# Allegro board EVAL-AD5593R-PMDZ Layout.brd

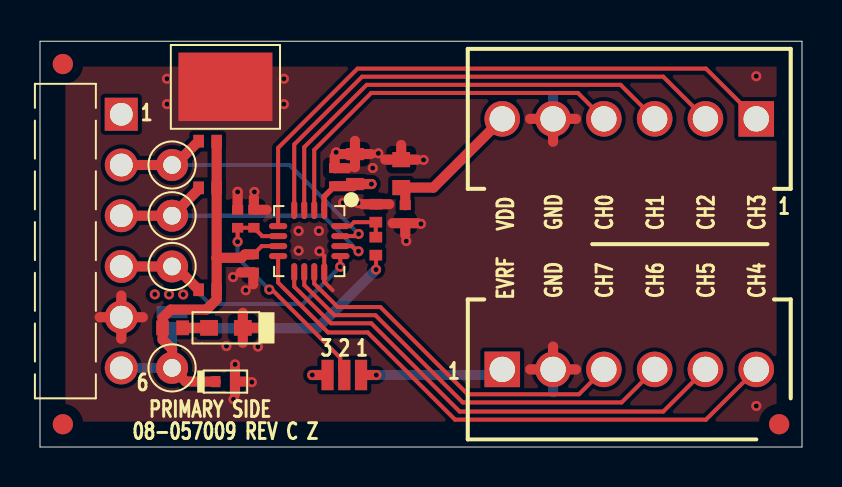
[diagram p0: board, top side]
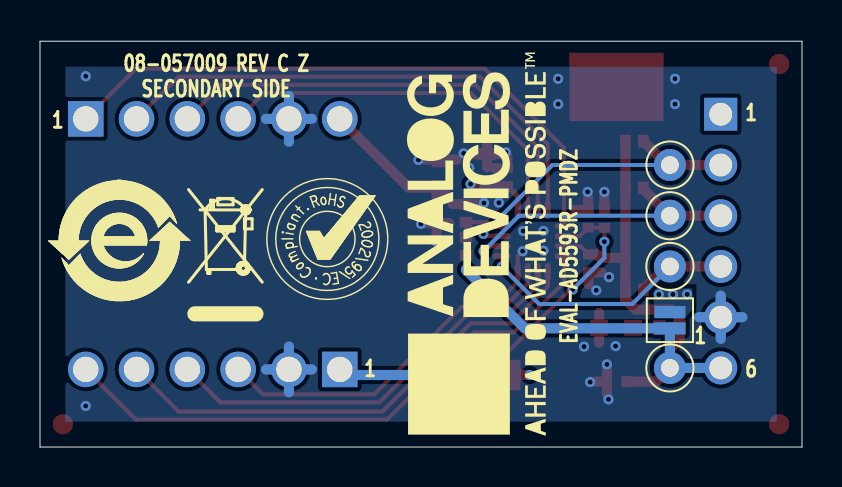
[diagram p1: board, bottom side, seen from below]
Outline 38.1 x 20.32 mm; copper layers: TOP, L2_GND, L3_PWR, BOTTOM. Coordinates in mm from the lower left corner of the outline.
Outline path: 0,20.32 0,0 38.1,0 38.1,20.32 0,20.32

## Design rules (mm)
constraint set DEFAULT: min track width 0.203

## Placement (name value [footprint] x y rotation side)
C1  1UF  [C0402]  10.69 11.43 270 top
C2  0.1UF  [C0402]  9.88 11.43 270 top
C3  0.1UF  [C0402]  14.73 13.51 90 top
C4  10UF  [C0603H47]  15.75 13.92 90 top
C5  0.1UF  [C0402]  10.67 9.19 270 top
C6  10UF  [C0603H47#2]  18.06 13.69 90 top
C7  0.1UF  [C0402]  18.26 11.66 270 top
D1  ESD9L5.0ST5G  [SOD923]  9.27 3.28 0 top
DS1  SML-D12P8WT86  [LED0603_A]  9.3 5.97 180 top
GND  5016  [CNKEY5016TP]  9.27 18.03 0 top
JP1  3PIN_SOLDER_JUMPER  [JPRSLD03]  15.21 3.61 180 top
NOREF  -  []  0 0 0 top
NOREF#2  -  []  38.1 0 90 top
NOREF#3  -  []  4.06 3.96 0 top
NOREF#4  -  []  0 20.32 270 top
NOREF#5  -  []  95.5 -55.6 0 top
NOREF#6  -  []  32.64 259.99 0 top
NOREF#7  -  [unnamed#2]  1.14 19.18 0 top
NOREF#8  -  [unnamed#2]  1.14 1.14 90 top
NOREF#9  -  []  0 20.32 0 top
NOREF#10  -  []  98.82 67.84 0 top
NOREF#11  -  []  38.1 20.32 180 top
NOREF#12  -  []  38.1 0 90 top
NOREF#13  -  []  -67.31 -123.04 0 top
NOREF#14  -  []  0 20.32 0 top
NOREF#15  -  []  19.43 36.39 0 top
NOREF#16  -  []  48.9 143.79 0 top
NOREF#17  -  [unnamed#2]  36.96 1.14 180 top
NOREF#18  -  []  0 0 0 top
NOREF#19  -  []  20.19 186 270 top
NOREF#20  -  []  38.1 0 0 top
NOREF#21  -  []  -67.18 -123.04 0 top
NOREF#22  -  []  4.06 3.96 0 top
NOREF#23  -  []  0 0 0 top
NOREF#24  -  []  29.03 6.35 180 bottom
NOREF#25  -  []  16.38 10.19 90 bottom
P1  TSW-106-25-F-S-RA  [CNHDRRA1X6H122]  4.06 16.66 270 top
P2  OSTVN06A150  [CNOSTVN06A1X0]  35.81 16.43 180 top
P3  OSTVN06A150  [CNOSTVN06A1X0]  23.11 3.89 0 top
P8  -  [JPSLD02]  6.6 6.35 90 bottom
R1  100K  [R0402]  16.79 11.71 90 top
R2  100K  [R0402]  8.38 15.32 180 top
R3  100K  [R0402]  8.38 7.87 180 top
R4  100K  [R0402]  8.38 12.98 180 top
R5  100K  [R0402]  16.79 10.06 90 top
R6  1K  [R0402]  6.63 5.97 0 top
RST  TP_VIA  [TPC63D35]  6.6 14.12 0 top
SCL  TP_VIA  [TPC63D35]  6.6 11.58 0 top
SDA  TP_VIA  [TPC63D35]  6.6 9.04 0 top
U1  AD5593RBCPZ  [QFN16_3X3_A]  13.46 10.31 180 top
VLOGIC  TP_VIA  [TPC63D35]  6.6 3.96 0 top

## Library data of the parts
C1 = CAP: User Part Number: UPN; Tolerance: 10; alternate symbols: C0402L; part number: CAP_SM-1UF,10V,10,E033897,C0402; tolerance: 10
C2 C3 C5 C7 = CAP: User Part Number: UPN; Tolerance: 10; alternate symbols: C0402L; part number: CAP_SM-0.1UF,16V,10,E027519,C0402; tolerance: 10
C4 = CAP: User Part Number: UPN; Tolerance: 10; alternate symbols: R0603L; part number: CAP_SM-10UF,10V,10,E034975,C0603H47; tolerance: 10
C6 = CAP: User Part Number: UPN; Tolerance: 10; alternate symbols: C0603L; part number: CAP_SM-10UF,10V,10,E034975,C0603H47; tolerance: 10
D1 = DIOZNR: User Part Number: UPN; Tolerance: N/A; alternate symbols: (); part number: DIOZNR_SM-ESD9L5.0ST5G,5V,N/A,E012879,SOD923; tolerance: N/A
DS1 = DIOLED: User Part Number: UPN; Tolerance: N/A; alternate symbols: (); part number: DIOLED_SM-SML-D12P8WT86,2.2V,N/A,E027457,LED0603_A; tolerance: N/A
GND = CNTP1P: Tolerance: N/A; User Part Number: UPN; alternate symbols: (); part number: CNTP1P_SM-5016,E005890,CNKEY5016TP; tolerance: N/A
JP1 = NC3P_JMPR: Tolerance: N/A; User Part Number: UPN; alternate symbols: (); part number: NC3P_JMPR_SM-3PIN_SOLDER_JUMPER,E005606,JPRSLD03; tolerance: N/A
P1 = CN6P: User Part Number: UPN; Tolerance: N/A; alternate symbols: (); part number: CN6P_TH-TSW-106-25-F-S-RA,E018547,CNHDRRA1X6H122; tolerance: N/A
P2 P3 = CN6P: User Part Number: UPN; Tolerance: N/A; alternate symbols: (); part number: CN6P_TH-OSTVN06A150,E039593,CNOSTVN06A1X0; tolerance: N/A
P8 = NC2P: User Part Number: UPN; Tolerance: N/A; alternate symbols: (); part number: NC2P_SM-JPSLD02,E006230,JPSLD02; tolerance: N/A
R1-R5 = RES: User Part Number: UPN; Tolerance: 1; alternate symbols: R0402L; part number: RES_SM-100K,E003796,1/16W,1,R0402; tolerance: 1
R6 = RES: User Part Number: UPN; Tolerance: 5; alternate symbols: (R0402L); part number: RES_SM-1K,E020936,1/16W,5,R0402; tolerance: 5
RST SCL SDA VLOGIC = NCTESTPAD: Tolerance: N/A; User Part Number: UPN; alternate symbols: (); part number: NCTESTPAD_TH-TP_VIA,E012149,TPC63D35; tolerance: N/A
U1 = AD5593R_V2: User Part Number: UPN; Tolerance: N/A; alternate symbols: (); part number: AD5593R_V2_SM-AD5593RBCPZ,E035069,QFN16_3X3_A; tolerance: N/A

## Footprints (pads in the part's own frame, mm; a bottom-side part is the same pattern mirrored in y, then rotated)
C0402
  rect 0.483x0.559 smd: 1(-0.45,0) 2(0.45,0)
C0603H47
  rect 0.61x0.889 smd: 1(-0.75,0) 2(0.75,0)
C0603H47#2
  rect 0.762x0.889 smd: 1(-0.7,0) 2(0.7,0)
CNHDRRA1X6H122
  rect 1.651x1.651 hole 1.143: 1(0,0)
  round 1.651 hole 1.143: 2(2.54,0) 3(5.08,0) 4(7.62,0) 5(10.16,0) 6(12.7,0)
CNKEY5016TP
  rect 4.699x3.429 smd: 1(0,0)
CNOSTVN06A1X0
  rect 1.778x1.778 hole 1.27: 1(0,0)
  round 1.778 hole 1.27: 2(2.54,0) 3(5.08,0) 4(7.62,0) 5(10.16,0) 6(12.7,0)
JPRSLD03
  rect 0.61x1.524 smd: 1(-0.838,0) 2(0,0) 3(0.838,0)
JPSLD02
  rect 0.61x1.549 smd: 1(-0.406,0) 2(0.406,0)
LED0603_A
  rect 0.889x0.787 smd: A(0.845,0) C(-0.845,0)
QFN16_3X3_A
  oval 0.305x0.914 smd: 1(-0.75,-1.557) 2(-0.25,-1.557) 3(0.25,-1.557) 4(0.75,-1.557) 9(0.75,1.557) 10(0.25,1.557) 11(-0.25,1.557) 12(-0.75,1.557)
  oval 0.914x0.305 smd: 5(1.557,-0.75) 6(1.557,-0.25) 7(1.557,0.25) 8(1.557,0.75) 13(-1.557,0.75) 14(-1.557,0.25) 15(-1.557,-0.25) 16(-1.557,-0.75)
R0402
  rect 0.533x0.635 smd: 1(-0.45,0) 2(0.45,0)
SOD923
  rect 0.457x0.559 smd: A(0.479,0) C(-0.479,0)
TPC63D35
  round 1.6 hole 0.889: 1(0,0)
unnamed#2
  round 1.016 smd: (0,0)

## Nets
GND: C1.1 C2.1 C3.2(N2) C4.2(N2) C5.2(N2) C6.2(N2) C7.2(N2) D1.A(P) DS1.C GND.1(N1) P1.5 P2.5 P3.2 R1.2(N2) U1.12
VDD: C3.1 C4.1 C6.1 C7.1 JP1.3 P2.6(N6) P8.2(N2) U1.1
A0: R1.1 R5.2(N2) U1.16
EXT_VREF: JP1.1 P3.1
I2C_SCL: P1.3 R4.2(N2) SCL.1(N1) U1.14
I2C_SDA: P1.4 R3.2(N2) SDA.1(N1) U1.13
I/O0: P2.4 U1.2
I/O1: P2.3 U1.3
I/O2: P2.2 U1.4
I/O3: P2.1 U1.5
I/O4: P3.6(N6) U1.8
I/O5: P3.5 U1.9
I/O6: P3.4 U1.10
I/O7: P3.3 U1.11
RESET: P1.2 R2.2(N2) RST.1(N1) U1.15
UNNAMED_2_DIOLED_I110_P: DS1.A(P) R6.2(N2)
VLOGIC: C5.1 D1.C P1.6(N6) P8.1 R2.1 R3.1 R4.1 R5.1 R6.1 U1.7 VLOGIC.1(N1)
VREF: C1.2(N2) C2.2(N2) JP1.2(COM) U1.6(VREF)

Pads without a net: P1 1

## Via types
v1: diameter 0.508, hole 0.254, TOP to BOTTOM, 39 vias

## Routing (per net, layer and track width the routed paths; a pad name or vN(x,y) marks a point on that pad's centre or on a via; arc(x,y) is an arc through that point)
GND: length 57.6
  TOP w0.203: 14.63,7.85 14.21,8.27 U1.12 14.21,9.56 v1(13.97,9.8)
  TOP w0.508: 4.06,5.42 P1.5 ; P1.5 5.14,6.5 ; P1.5 4.06,7.58 ; P1.5 2.98,6.5 ; 14.95,14.67 C4.2 ; C4.2 15.75,14.01 ; C4.2 16.55,14.67 ; C4.2 15.75,15.33 ; D1.A 9.75,3.91 ; D1.A 9.75,2.64 ; D1.A 10.33,3.28 ; P3.2 25.65,5.03 ; P3.2 24.51,3.89 ; P3.2 26.8,3.89 ; 10.67,8.15 C5.2 10.03,8.74 ; C6.2 18.86,14.39 ; C6.2 17.26,14.39 ; C6.2 18.06,15.13 ; 17.63,11.21 C7.2 ; C7.2 18.9,11.21 ; C7.2 18.26,10.61 ; P2.5 26.8,16.43 ; P2.5 24.51,16.43 ; P2.5 25.65,15.29 ; 17.46,12.16 R1.2 16.12,12.16 ; 15.37,13.96 C3.2 14.73,14.56 ; DS1.C 10.94,5.97 ; DS1.C 10.14,6.72 ; DS1.C 10.14,5.22 ; C2.1 v1(9.88,12.78) ; 10.69,12.48 C1.1 11.33,11.88
  L2_GND w0.508: P2.5 26.8,16.43 ; P2.5 25.65,15.29 ; P2.5 24.51,16.43 ; P2.5 25.65,17.58 ; P3.2 25.65,5.03 ; P3.2 25.65,2.74 ; P3.2 24.51,3.89 ; P3.2 26.8,3.89 ; P1.5 4.06,7.58 ; P1.5 5.14,6.5 ; P1.5 2.98,6.5 ; P1.5 4.06,5.42
  BOTTOM w0.508: P1.5 4.06,7.58 ; P1.5 2.98,6.5 ; P1.5 5.14,6.5 ; P1.5 4.06,5.42 ; P2.5 26.8,16.43 ; P2.5 25.65,15.29 ; P2.5 24.51,16.43 ; P2.5 25.65,17.58 ; P3.2 26.8,3.89 ; P3.2 25.65,5.03 ; P3.2 25.65,2.74 ; P3.2 24.51,3.89
  vias: v1(6.35,18.44) v1(6.35,17.17) v1(9.32,5.05) v1(9.65,8.51) v1(9.68,2.39) v1(9.75,4.14) v1(10.29,7.85) v1(10.59,3.25) v1(10.72,12.78) v1(10.9,5.03) v1(12.19,18.44) v1(12.19,17.17) v1(12.93,10.82) v1(12.93,9.83) v1(13.94,10.82) v1(14.81,14.76) v1(15.16,12.24) v1(15.9,12.22) v1(16.64,13.97) v1(16.92,14.71) v1(18.31,10.31) v1(19.05,11.18) v1(19.18,14.38) v1(35.81,18.57) v1(35.81,2.06)
VDD: length 16.1
  TOP w0.279: U1.1 14.21,12.54 C3.1
  TOP w0.508: v1(16.57,13.17) C4.1 15.64,13.06 C3.1 ; C7.1 18.26,12.79 C6.1 19.67,12.99 P2.6 ; JP1.3 v1(13.61,3.61)
  L3_PWR w0.508: 23.11,15.29 P2.6 ; P2.6 21.97,16.43 ; P2.6 24.26,16.43 ; P2.6 23.11,17.58
  vias: v1(5.74,7.65) v1(6.45,7.65) v1(7.16,7.64)
A0: length 2.6
  TOP w0.203: U1.16 15.51,11.06 15.7,11.26 R1.1 R5.2
EXT_VREF: length 7.2
  TOP w0.508: JP1.1 v1(16.81,3.61)
  BOTTOM w0.508: P3.1 22.83,3.61 v1(16.81,3.61)
I2C_SCL: length 15.6
  TOP w0.203: U1.14 15.59,10.06 15.85,9.8 v1(15.93,9.8)
  TOP w0.508: P1.3 SCL.1 7.93,12.91 R4.2
  BOTTOM w0.203: v1(15.93,9.8) 14.15,11.58 SCL.1
I2C_SDA: length 14.8
  TOP w0.203: v1(15.01,9.03) 15.01,9.55 U1.13
  TOP w0.508: P1.4 SDA.1 6.76,9.04 R3.2
  BOTTOM w0.203: SDA.1 8.48,7.16 13.15,7.16 v1(15.01,9.03)
I/O0: length 19.2
  TOP w0.203: U1.2 13.71,14.88 16.56,17.73 26.9,17.73 P2.4
I/O1: length 22.7
  TOP w0.203: P2.3 29.03,18.14 16.33,18.14 13.21,15.02 U1.3
I/O2: length 26.1
  TOP w0.203: P2.2 31.16,18.54 16.1,18.54 12.71,15.15 U1.4
I/O3: length 30.5
  TOP w0.203: P2.1 33.3,18.95 15.87,18.95 11.9,14.98 U1.5
I/O4: length 29.1
  TOP w0.203: P3.6 33.3,1.37 20.75,1.37 16.38,5.74 14.4,5.74 11.9,8.24 U1.8
I/O5: length 24.7
  TOP w0.203: U1.9 12.71,8.03 14.55,6.2 16.56,6.2 20.98,1.78 31.16,1.78 P3.5
I/O6: length 21.3
  TOP w0.203: P3.4 29.08,2.24 21.13,2.24 16.77,6.6 14.72,6.6 13.21,8.11 U1.10
I/O7: length 17.9
  TOP w0.203: U1.11 13.71,8.18 14.88,7.01 17.02,7.01 21.39,2.64 26.95,2.64 P3.3
RESET: length 16.1
  TOP w0.203: v1(15.93,10.67) 15.82,10.67 15.72,10.56 U1.15
  TOP w0.508: R2.2 6.74,14.12 RST.1 P1.2
  BOTTOM w0.203: RST.1 12.48,14.12 v1(15.93,10.67)
UNNAMED_2_DIOLED_I110_P: length 1.3
  TOP w0.508: R6.2 DS1.A
VLOGIC: length 36.2
  TOP w0.203: U1.7 11.09,10.06 C5.1 ; v1(16.8,8.88) 16.8,9.6 R5.1
  TOP w0.508: 8.84,9.47 8.83,9.47 R3.1 8.83,7.39 8.32,6.88 6.54,6.88 6.13,6.48 R6.1 6.13,5.38 6.6,4.9 VLOGIC.1 7.29,3.28 D1.C ; 8.84,9.47 8.83,9.48 R4.1 R2.1 ; 8.84,9.47 10.08,9.47 10.25,9.64 C5.1
  BOTTOM w0.508: P1.6 VLOGIC.1 P8.1 13.86,5.94 v1(16.8,8.88)
VREF: length 11.9
  TOP w0.203: JP1.2 15.01,3.81 15.01,4.47 11.6,7.88 v1(11.47,7.88) ; v1(9.88,10.28) C2.2 C1.2 11.11,10.56 U1.6
  BOTTOM w0.203: v1(11.47,7.88) 9.88,9.47 v1(9.88,10.28)

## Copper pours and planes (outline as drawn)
GND on TOP: 1.27,1.27 36.83,1.27 36.83,19.05 1.27,19.05 ; 1 cut-out
GND on BOTTOM, L2_GND: 1.27,1.27 36.83,1.27 36.83,19.05 1.27,19.05
VDD on BOTTOM: 5.49,7.95 5.49,6.86 5.84,6.5 7.42,6.5 7.42,7.95
VDD on L3_PWR: 1.27,1.27 36.83,1.27 36.83,19.05 1.27,19.05

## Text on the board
Ref Des/Silkscreen Bottom: EVAL-AD5593R-PMDZ
User.Comments: 5.    ASSEMBLY VENDOR MUST SOLDER SHORT ON DEFAULT POSITION PIN 1 & 2 | OF THE COPONENT JP1.
Ref Des/Assembly Top: 3 | 2 | 1
Ref Des/Silkscreen Top: VDD | EVRF | GND | CH0 | CH7 | CH1 | CH6 | CH2 | CH5 | CH3 | CH4
PAGE_OUTLINE: 05MAR19 | B | C | AS PER ECR-089173 | AS PER ECR-090069 | 28JUN19 | 06SEP19 | J.PENAFLOR | EVAL-AD5593R-PMDZ
DIMENSION: " " | (REF) | DIA MAX
User.12: 1 | OF THE COPONENT P8. | 6.    ASSEMBLY VENDOR MUST SOLDER SHORT ON DEFAULT POSITION PIN 1 & 2
User.17: L2 GND | 08-      -07
User.18: L3 PWR | 08-      -08
User.45: FIGURE | SIZE | 10.0 | 35.0 | 45.0 | 50.0 | PLATED | DRILL CHART: TOP to BOTTOM | ALL UNITS ARE IN MILS | QTY | 39 | 4 | 6 | 12 | TOLERANCE/NOTES
